VERSION 5.8 ;
BUSBITCHARS "[]" ;
DIVIDERCHAR "/" ;
UNITS
    DATABASE MICRONS 2000 ;
END UNITS

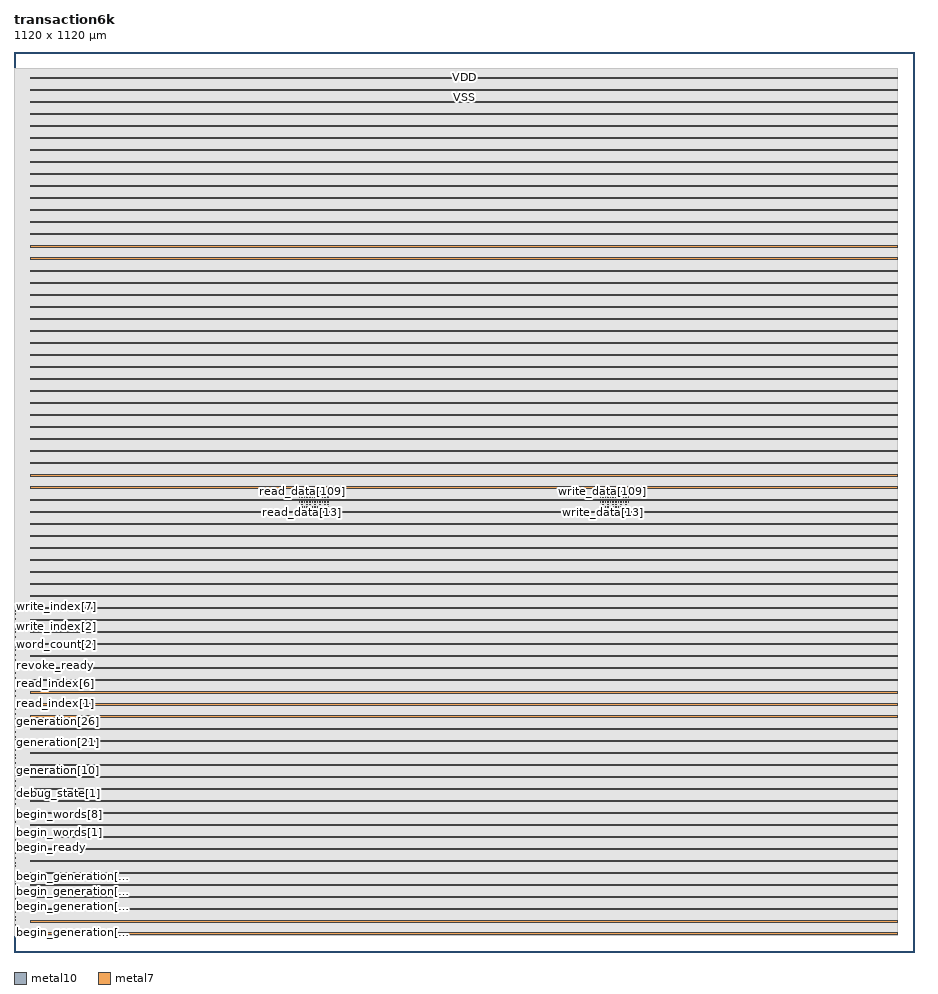
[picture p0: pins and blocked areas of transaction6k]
MACRO transaction6k
  FOREIGN transaction6k 0 0 ;
  CLASS BLOCK ;
  SIZE 1120 BY 1120 ;
  PIN begin_generation[0]
    DIRECTION INPUT ;
    USE SIGNAL ;
    PORT
      LAYER metal10 ;
        RECT  1.295 20.47 2.095 21.27 ;
    END
  END begin_generation[0]
  PIN begin_generation[10]
    DIRECTION INPUT ;
    USE SIGNAL ;
    PORT
      LAYER metal10 ;
        RECT  1.295 52.47 2.095 53.27 ;
    END
  END begin_generation[10]
  PIN begin_generation[11]
    DIRECTION INPUT ;
    USE SIGNAL ;
    PORT
      LAYER metal10 ;
        RECT  1.295 55.67 2.095 56.47 ;
    END
  END begin_generation[11]
  PIN begin_generation[12]
    DIRECTION INPUT ;
    USE SIGNAL ;
    PORT
      LAYER metal10 ;
        RECT  1.295 58.87 2.095 59.67 ;
    END
  END begin_generation[12]
  PIN begin_generation[13]
    DIRECTION INPUT ;
    USE SIGNAL ;
    PORT
      LAYER metal10 ;
        RECT  1.295 62.07 2.095 62.87 ;
    END
  END begin_generation[13]
  PIN begin_generation[14]
    DIRECTION INPUT ;
    USE SIGNAL ;
    PORT
      LAYER metal10 ;
        RECT  1.295 65.27 2.095 66.07 ;
    END
  END begin_generation[14]
  PIN begin_generation[15]
    DIRECTION INPUT ;
    USE SIGNAL ;
    PORT
      LAYER metal10 ;
        RECT  1.295 68.47 2.095 69.27 ;
    END
  END begin_generation[15]
  PIN begin_generation[16]
    DIRECTION INPUT ;
    USE SIGNAL ;
    PORT
      LAYER metal10 ;
        RECT  1.295 71.67 2.095 72.47 ;
    END
  END begin_generation[16]
  PIN begin_generation[17]
    DIRECTION INPUT ;
    USE SIGNAL ;
    PORT
      LAYER metal10 ;
        RECT  1.295 74.87 2.095 75.67 ;
    END
  END begin_generation[17]
  PIN begin_generation[18]
    DIRECTION INPUT ;
    USE SIGNAL ;
    PORT
      LAYER metal10 ;
        RECT  1.295 78.07 2.095 78.87 ;
    END
  END begin_generation[18]
  PIN begin_generation[19]
    DIRECTION INPUT ;
    USE SIGNAL ;
    PORT
      LAYER metal10 ;
        RECT  1.295 81.27 2.095 82.07 ;
    END
  END begin_generation[19]
  PIN begin_generation[1]
    DIRECTION INPUT ;
    USE SIGNAL ;
    PORT
      LAYER metal10 ;
        RECT  1.295 23.67 2.095 24.47 ;
    END
  END begin_generation[1]
  PIN begin_generation[20]
    DIRECTION INPUT ;
    USE SIGNAL ;
    PORT
      LAYER metal10 ;
        RECT  1.295 84.47 2.095 85.27 ;
    END
  END begin_generation[20]
  PIN begin_generation[21]
    DIRECTION INPUT ;
    USE SIGNAL ;
    PORT
      LAYER metal10 ;
        RECT  1.295 87.67 2.095 88.47 ;
    END
  END begin_generation[21]
  PIN begin_generation[22]
    DIRECTION INPUT ;
    USE SIGNAL ;
    PORT
      LAYER metal10 ;
        RECT  1.295 90.87 2.095 91.67 ;
    END
  END begin_generation[22]
  PIN begin_generation[23]
    DIRECTION INPUT ;
    USE SIGNAL ;
    PORT
      LAYER metal10 ;
        RECT  1.295 94.07 2.095 94.87 ;
    END
  END begin_generation[23]
  PIN begin_generation[24]
    DIRECTION INPUT ;
    USE SIGNAL ;
    PORT
      LAYER metal10 ;
        RECT  1.295 97.27 2.095 98.07 ;
    END
  END begin_generation[24]
  PIN begin_generation[25]
    DIRECTION INPUT ;
    USE SIGNAL ;
    PORT
      LAYER metal10 ;
        RECT  1.295 100.47 2.095 101.27 ;
    END
  END begin_generation[25]
  PIN begin_generation[26]
    DIRECTION INPUT ;
    USE SIGNAL ;
    PORT
      LAYER metal10 ;
        RECT  1.295 103.67 2.095 104.47 ;
    END
  END begin_generation[26]
  PIN begin_generation[27]
    DIRECTION INPUT ;
    USE SIGNAL ;
    PORT
      LAYER metal10 ;
        RECT  1.295 106.87 2.095 107.67 ;
    END
  END begin_generation[27]
  PIN begin_generation[28]
    DIRECTION INPUT ;
    USE SIGNAL ;
    PORT
      LAYER metal10 ;
        RECT  1.295 110.07 2.095 110.87 ;
    END
  END begin_generation[28]
  PIN begin_generation[29]
    DIRECTION INPUT ;
    USE SIGNAL ;
    PORT
      LAYER metal10 ;
        RECT  1.295 113.27 2.095 114.07 ;
    END
  END begin_generation[29]
  PIN begin_generation[2]
    DIRECTION INPUT ;
    USE SIGNAL ;
    PORT
      LAYER metal10 ;
        RECT  1.295 26.87 2.095 27.67 ;
    END
  END begin_generation[2]
  PIN begin_generation[30]
    DIRECTION INPUT ;
    USE SIGNAL ;
    PORT
      LAYER metal10 ;
        RECT  1.295 116.47 2.095 117.27 ;
    END
  END begin_generation[30]
  PIN begin_generation[31]
    DIRECTION INPUT ;
    USE SIGNAL ;
    PORT
      LAYER metal10 ;
        RECT  1.295 119.67 2.095 120.47 ;
    END
  END begin_generation[31]
  PIN begin_generation[3]
    DIRECTION INPUT ;
    USE SIGNAL ;
    PORT
      LAYER metal10 ;
        RECT  1.295 30.07 2.095 30.87 ;
    END
  END begin_generation[3]
  PIN begin_generation[4]
    DIRECTION INPUT ;
    USE SIGNAL ;
    PORT
      LAYER metal10 ;
        RECT  1.295 33.27 2.095 34.07 ;
    END
  END begin_generation[4]
  PIN begin_generation[5]
    DIRECTION INPUT ;
    USE SIGNAL ;
    PORT
      LAYER metal10 ;
        RECT  1.295 36.47 2.095 37.27 ;
    END
  END begin_generation[5]
  PIN begin_generation[6]
    DIRECTION INPUT ;
    USE SIGNAL ;
    PORT
      LAYER metal10 ;
        RECT  1.295 39.67 2.095 40.47 ;
    END
  END begin_generation[6]
  PIN begin_generation[7]
    DIRECTION INPUT ;
    USE SIGNAL ;
    PORT
      LAYER metal10 ;
        RECT  1.295 42.87 2.095 43.67 ;
    END
  END begin_generation[7]
  PIN begin_generation[8]
    DIRECTION INPUT ;
    USE SIGNAL ;
    PORT
      LAYER metal10 ;
        RECT  1.295 46.07 2.095 46.87 ;
    END
  END begin_generation[8]
  PIN begin_generation[9]
    DIRECTION INPUT ;
    USE SIGNAL ;
    PORT
      LAYER metal10 ;
        RECT  1.295 49.27 2.095 50.07 ;
    END
  END begin_generation[9]
  PIN begin_owner[0]
    DIRECTION INPUT ;
    USE SIGNAL ;
    PORT
      LAYER metal10 ;
        RECT  1.295 122.87 2.095 123.67 ;
    END
  END begin_owner[0]
  PIN begin_owner[1]
    DIRECTION INPUT ;
    USE SIGNAL ;
    PORT
      LAYER metal10 ;
        RECT  1.295 126.07 2.095 126.87 ;
    END
  END begin_owner[1]
  PIN begin_ready
    DIRECTION OUTPUT ;
    USE SIGNAL ;
    PORT
      LAYER metal10 ;
        RECT  1.295 129.27 2.095 130.07 ;
    END
  END begin_ready
  PIN begin_valid
    DIRECTION INPUT ;
    USE SIGNAL ;
    PORT
      LAYER metal10 ;
        RECT  1.295 132.47 2.095 133.27 ;
    END
  END begin_valid
  PIN begin_words[0]
    DIRECTION INPUT ;
    USE SIGNAL ;
    PORT
      LAYER metal10 ;
        RECT  1.295 135.67 2.095 136.47 ;
    END
  END begin_words[0]
  PIN begin_words[1]
    DIRECTION INPUT ;
    USE SIGNAL ;
    PORT
      LAYER metal10 ;
        RECT  1.295 138.87 2.095 139.67 ;
    END
  END begin_words[1]
  PIN begin_words[2]
    DIRECTION INPUT ;
    USE SIGNAL ;
    PORT
      LAYER metal10 ;
        RECT  1.295 142.07 2.095 142.87 ;
    END
  END begin_words[2]
  PIN begin_words[3]
    DIRECTION INPUT ;
    USE SIGNAL ;
    PORT
      LAYER metal10 ;
        RECT  1.295 145.27 2.095 146.07 ;
    END
  END begin_words[3]
  PIN begin_words[4]
    DIRECTION INPUT ;
    USE SIGNAL ;
    PORT
      LAYER metal10 ;
        RECT  1.295 148.47 2.095 149.27 ;
    END
  END begin_words[4]
  PIN begin_words[5]
    DIRECTION INPUT ;
    USE SIGNAL ;
    PORT
      LAYER metal10 ;
        RECT  1.295 151.67 2.095 152.47 ;
    END
  END begin_words[5]
  PIN begin_words[6]
    DIRECTION INPUT ;
    USE SIGNAL ;
    PORT
      LAYER metal10 ;
        RECT  1.295 154.87 2.095 155.67 ;
    END
  END begin_words[6]
  PIN begin_words[7]
    DIRECTION INPUT ;
    USE SIGNAL ;
    PORT
      LAYER metal10 ;
        RECT  1.295 158.07 2.095 158.87 ;
    END
  END begin_words[7]
  PIN begin_words[8]
    DIRECTION INPUT ;
    USE SIGNAL ;
    PORT
      LAYER metal10 ;
        RECT  1.295 161.27 2.095 162.07 ;
    END
  END begin_words[8]
  PIN begin_words[9]
    DIRECTION INPUT ;
    USE SIGNAL ;
    PORT
      LAYER metal10 ;
        RECT  1.295 164.47 2.095 165.27 ;
    END
  END begin_words[9]
  PIN busy
    DIRECTION OUTPUT ;
    USE SIGNAL ;
    PORT
      LAYER metal10 ;
        RECT  1.295 167.67 2.095 168.47 ;
    END
  END busy
  PIN clk
    DIRECTION INPUT ;
    USE SIGNAL ;
    PORT
      LAYER metal10 ;
        RECT  1.295 170.87 2.095 171.67 ;
    END
  END clk
  PIN commit_ready
    DIRECTION OUTPUT ;
    USE SIGNAL ;
    PORT
      LAYER metal10 ;
        RECT  1.295 174.07 2.095 174.87 ;
    END
  END commit_ready
  PIN commit_valid
    DIRECTION INPUT ;
    USE SIGNAL ;
    PORT
      LAYER metal10 ;
        RECT  1.295 177.27 2.095 178.07 ;
    END
  END commit_valid
  PIN committed
    DIRECTION OUTPUT ;
    USE SIGNAL ;
    PORT
      LAYER metal10 ;
        RECT  1.295 180.47 2.095 181.27 ;
    END
  END committed
  PIN debug_state[0]
    DIRECTION OUTPUT ;
    USE SIGNAL ;
    PORT
      LAYER metal10 ;
        RECT  1.295 183.67 2.095 184.47 ;
    END
  END debug_state[0]
  PIN debug_state[1]
    DIRECTION OUTPUT ;
    USE SIGNAL ;
    PORT
      LAYER metal10 ;
        RECT  1.295 186.87 2.095 187.67 ;
    END
  END debug_state[1]
  PIN debug_state[2]
    DIRECTION OUTPUT ;
    USE SIGNAL ;
    PORT
      LAYER metal10 ;
        RECT  1.295 190.07 2.095 190.87 ;
    END
  END debug_state[2]
  PIN generation[0]
    DIRECTION OUTPUT ;
    USE SIGNAL ;
    PORT
      LAYER metal10 ;
        RECT  1.295 193.27 2.095 194.07 ;
    END
  END generation[0]
  PIN generation[10]
    DIRECTION OUTPUT ;
    USE SIGNAL ;
    PORT
      LAYER metal10 ;
        RECT  1.295 225.27 2.095 226.07 ;
    END
  END generation[10]
  PIN generation[11]
    DIRECTION OUTPUT ;
    USE SIGNAL ;
    PORT
      LAYER metal10 ;
        RECT  1.295 228.47 2.095 229.27 ;
    END
  END generation[11]
  PIN generation[12]
    DIRECTION OUTPUT ;
    USE SIGNAL ;
    PORT
      LAYER metal10 ;
        RECT  1.295 231.67 2.095 232.47 ;
    END
  END generation[12]
  PIN generation[13]
    DIRECTION OUTPUT ;
    USE SIGNAL ;
    PORT
      LAYER metal10 ;
        RECT  1.295 234.87 2.095 235.67 ;
    END
  END generation[13]
  PIN generation[14]
    DIRECTION OUTPUT ;
    USE SIGNAL ;
    PORT
      LAYER metal10 ;
        RECT  1.295 238.07 2.095 238.87 ;
    END
  END generation[14]
  PIN generation[15]
    DIRECTION OUTPUT ;
    USE SIGNAL ;
    PORT
      LAYER metal10 ;
        RECT  1.295 241.27 2.095 242.07 ;
    END
  END generation[15]
  PIN generation[16]
    DIRECTION OUTPUT ;
    USE SIGNAL ;
    PORT
      LAYER metal10 ;
        RECT  1.295 244.47 2.095 245.27 ;
    END
  END generation[16]
  PIN generation[17]
    DIRECTION OUTPUT ;
    USE SIGNAL ;
    PORT
      LAYER metal10 ;
        RECT  1.295 247.67 2.095 248.47 ;
    END
  END generation[17]
  PIN generation[18]
    DIRECTION OUTPUT ;
    USE SIGNAL ;
    PORT
      LAYER metal10 ;
        RECT  1.295 250.87 2.095 251.67 ;
    END
  END generation[18]
  PIN generation[19]
    DIRECTION OUTPUT ;
    USE SIGNAL ;
    PORT
      LAYER metal10 ;
        RECT  1.295 254.07 2.095 254.87 ;
    END
  END generation[19]
  PIN generation[1]
    DIRECTION OUTPUT ;
    USE SIGNAL ;
    PORT
      LAYER metal10 ;
        RECT  1.295 196.47 2.095 197.27 ;
    END
  END generation[1]
  PIN generation[20]
    DIRECTION OUTPUT ;
    USE SIGNAL ;
    PORT
      LAYER metal10 ;
        RECT  1.295 257.27 2.095 258.07 ;
    END
  END generation[20]
  PIN generation[21]
    DIRECTION OUTPUT ;
    USE SIGNAL ;
    PORT
      LAYER metal10 ;
        RECT  1.295 260.47 2.095 261.27 ;
    END
  END generation[21]
  PIN generation[22]
    DIRECTION OUTPUT ;
    USE SIGNAL ;
    PORT
      LAYER metal10 ;
        RECT  1.295 263.67 2.095 264.47 ;
    END
  END generation[22]
  PIN generation[23]
    DIRECTION OUTPUT ;
    USE SIGNAL ;
    PORT
      LAYER metal10 ;
        RECT  1.295 266.87 2.095 267.67 ;
    END
  END generation[23]
  PIN generation[24]
    DIRECTION OUTPUT ;
    USE SIGNAL ;
    PORT
      LAYER metal10 ;
        RECT  1.295 270.07 2.095 270.87 ;
    END
  END generation[24]
  PIN generation[25]
    DIRECTION OUTPUT ;
    USE SIGNAL ;
    PORT
      LAYER metal10 ;
        RECT  1.295 273.27 2.095 274.07 ;
    END
  END generation[25]
  PIN generation[26]
    DIRECTION OUTPUT ;
    USE SIGNAL ;
    PORT
      LAYER metal10 ;
        RECT  1.295 276.47 2.095 277.27 ;
    END
  END generation[26]
  PIN generation[27]
    DIRECTION OUTPUT ;
    USE SIGNAL ;
    PORT
      LAYER metal10 ;
        RECT  1.295 279.67 2.095 280.47 ;
    END
  END generation[27]
  PIN generation[28]
    DIRECTION OUTPUT ;
    USE SIGNAL ;
    PORT
      LAYER metal10 ;
        RECT  1.295 282.87 2.095 283.67 ;
    END
  END generation[28]
  PIN generation[29]
    DIRECTION OUTPUT ;
    USE SIGNAL ;
    PORT
      LAYER metal10 ;
        RECT  1.295 286.07 2.095 286.87 ;
    END
  END generation[29]
  PIN generation[2]
    DIRECTION OUTPUT ;
    USE SIGNAL ;
    PORT
      LAYER metal10 ;
        RECT  1.295 199.67 2.095 200.47 ;
    END
  END generation[2]
  PIN generation[30]
    DIRECTION OUTPUT ;
    USE SIGNAL ;
    PORT
      LAYER metal10 ;
        RECT  1.295 289.27 2.095 290.07 ;
    END
  END generation[30]
  PIN generation[31]
    DIRECTION OUTPUT ;
    USE SIGNAL ;
    PORT
      LAYER metal10 ;
        RECT  1.295 292.47 2.095 293.27 ;
    END
  END generation[31]
  PIN generation[3]
    DIRECTION OUTPUT ;
    USE SIGNAL ;
    PORT
      LAYER metal10 ;
        RECT  1.295 202.87 2.095 203.67 ;
    END
  END generation[3]
  PIN generation[4]
    DIRECTION OUTPUT ;
    USE SIGNAL ;
    PORT
      LAYER metal10 ;
        RECT  1.295 206.07 2.095 206.87 ;
    END
  END generation[4]
  PIN generation[5]
    DIRECTION OUTPUT ;
    USE SIGNAL ;
    PORT
      LAYER metal10 ;
        RECT  1.295 209.27 2.095 210.07 ;
    END
  END generation[5]
  PIN generation[6]
    DIRECTION OUTPUT ;
    USE SIGNAL ;
    PORT
      LAYER metal10 ;
        RECT  1.295 212.47 2.095 213.27 ;
    END
  END generation[6]
  PIN generation[7]
    DIRECTION OUTPUT ;
    USE SIGNAL ;
    PORT
      LAYER metal10 ;
        RECT  1.295 215.67 2.095 216.47 ;
    END
  END generation[7]
  PIN generation[8]
    DIRECTION OUTPUT ;
    USE SIGNAL ;
    PORT
      LAYER metal10 ;
        RECT  1.295 218.87 2.095 219.67 ;
    END
  END generation[8]
  PIN generation[9]
    DIRECTION OUTPUT ;
    USE SIGNAL ;
    PORT
      LAYER metal10 ;
        RECT  1.295 222.07 2.095 222.87 ;
    END
  END generation[9]
  PIN owner[0]
    DIRECTION OUTPUT ;
    USE SIGNAL ;
    PORT
      LAYER metal10 ;
        RECT  1.295 295.67 2.095 296.47 ;
    END
  END owner[0]
  PIN owner[1]
    DIRECTION OUTPUT ;
    USE SIGNAL ;
    PORT
      LAYER metal10 ;
        RECT  1.295 298.87 2.095 299.67 ;
    END
  END owner[1]
  PIN protocol_error
    DIRECTION OUTPUT ;
    USE SIGNAL ;
    PORT
      LAYER metal10 ;
        RECT  1.295 302.07 2.095 302.87 ;
    END
  END protocol_error
  PIN read_data[0]
    DIRECTION OUTPUT ;
    USE SIGNAL ;
    PORT
      LAYER metal10 ;
        RECT  354.895 543.67 355.695 544.47 ;
    END
  END read_data[0]
  PIN read_data[100]
    DIRECTION OUTPUT ;
    USE SIGNAL ;
    PORT
      LAYER metal10 ;
        RECT  367.695 569.27 368.495 570.07 ;
    END
  END read_data[100]
  PIN read_data[101]
    DIRECTION OUTPUT ;
    USE SIGNAL ;
    PORT
      LAYER metal10 ;
        RECT  370.895 569.27 371.695 570.07 ;
    END
  END read_data[101]
  PIN read_data[102]
    DIRECTION OUTPUT ;
    USE SIGNAL ;
    PORT
      LAYER metal10 ;
        RECT  374.095 569.27 374.895 570.07 ;
    END
  END read_data[102]
  PIN read_data[103]
    DIRECTION OUTPUT ;
    USE SIGNAL ;
    PORT
      LAYER metal10 ;
        RECT  377.295 569.27 378.095 570.07 ;
    END
  END read_data[103]
  PIN read_data[104]
    DIRECTION OUTPUT ;
    USE SIGNAL ;
    PORT
      LAYER metal10 ;
        RECT  380.495 569.27 381.295 570.07 ;
    END
  END read_data[104]
  PIN read_data[105]
    DIRECTION OUTPUT ;
    USE SIGNAL ;
    PORT
      LAYER metal10 ;
        RECT  383.695 569.27 384.495 570.07 ;
    END
  END read_data[105]
  PIN read_data[106]
    DIRECTION OUTPUT ;
    USE SIGNAL ;
    PORT
      LAYER metal10 ;
        RECT  386.895 569.27 387.695 570.07 ;
    END
  END read_data[106]
  PIN read_data[107]
    DIRECTION OUTPUT ;
    USE SIGNAL ;
    PORT
      LAYER metal10 ;
        RECT  390.095 569.27 390.895 570.07 ;
    END
  END read_data[107]
  PIN read_data[108]
    DIRECTION OUTPUT ;
    USE SIGNAL ;
    PORT
      LAYER metal10 ;
        RECT  354.895 572.47 355.695 573.27 ;
    END
  END read_data[108]
  PIN read_data[109]
    DIRECTION OUTPUT ;
    USE SIGNAL ;
    PORT
      LAYER metal10 ;
        RECT  358.095 572.47 358.895 573.27 ;
    END
  END read_data[109]
  PIN read_data[10]
    DIRECTION OUTPUT ;
    USE SIGNAL ;
    PORT
      LAYER metal10 ;
        RECT  386.895 543.67 387.695 544.47 ;
    END
  END read_data[10]
  PIN read_data[110]
    DIRECTION OUTPUT ;
    USE SIGNAL ;
    PORT
      LAYER metal10 ;
        RECT  361.295 572.47 362.095 573.27 ;
    END
  END read_data[110]
  PIN read_data[111]
    DIRECTION OUTPUT ;
    USE SIGNAL ;
    PORT
      LAYER metal10 ;
        RECT  364.495 572.47 365.295 573.27 ;
    END
  END read_data[111]
  PIN read_data[112]
    DIRECTION OUTPUT ;
    USE SIGNAL ;
    PORT
      LAYER metal10 ;
        RECT  367.695 572.47 368.495 573.27 ;
    END
  END read_data[112]
  PIN read_data[113]
    DIRECTION OUTPUT ;
    USE SIGNAL ;
    PORT
      LAYER metal10 ;
        RECT  370.895 572.47 371.695 573.27 ;
    END
  END read_data[113]
  PIN read_data[114]
    DIRECTION OUTPUT ;
    USE SIGNAL ;
    PORT
      LAYER metal10 ;
        RECT  374.095 572.47 374.895 573.27 ;
    END
  END read_data[114]
  PIN read_data[115]
    DIRECTION OUTPUT ;
    USE SIGNAL ;
    PORT
      LAYER metal10 ;
        RECT  377.295 572.47 378.095 573.27 ;
    END
  END read_data[115]
  PIN read_data[116]
    DIRECTION OUTPUT ;
    USE SIGNAL ;
    PORT
      LAYER metal10 ;
        RECT  380.495 572.47 381.295 573.27 ;
    END
  END read_data[116]
  PIN read_data[117]
    DIRECTION OUTPUT ;
    USE SIGNAL ;
    PORT
      LAYER metal10 ;
        RECT  383.695 572.47 384.495 573.27 ;
    END
  END read_data[117]
  PIN read_data[118]
    DIRECTION OUTPUT ;
    USE SIGNAL ;
    PORT
      LAYER metal10 ;
        RECT  386.895 572.47 387.695 573.27 ;
    END
  END read_data[118]
  PIN read_data[119]
    DIRECTION OUTPUT ;
    USE SIGNAL ;
    PORT
      LAYER metal10 ;
        RECT  390.095 572.47 390.895 573.27 ;
    END
  END read_data[119]
  PIN read_data[11]
    DIRECTION OUTPUT ;
    USE SIGNAL ;
    PORT
      LAYER metal10 ;
        RECT  390.095 543.67 390.895 544.47 ;
    END
  END read_data[11]
  PIN read_data[120]
    DIRECTION OUTPUT ;
    USE SIGNAL ;
    PORT
      LAYER metal10 ;
        RECT  354.895 575.67 355.695 576.47 ;
    END
  END read_data[120]
  PIN read_data[121]
    DIRECTION OUTPUT ;
    USE SIGNAL ;
    PORT
      LAYER metal10 ;
        RECT  358.095 575.67 358.895 576.47 ;
    END
  END read_data[121]
  PIN read_data[122]
    DIRECTION OUTPUT ;
    USE SIGNAL ;
    PORT
      LAYER metal10 ;
        RECT  361.295 575.67 362.095 576.47 ;
    END
  END read_data[122]
  PIN read_data[123]
    DIRECTION OUTPUT ;
    USE SIGNAL ;
    PORT
      LAYER metal10 ;
        RECT  364.495 575.67 365.295 576.47 ;
    END
  END read_data[123]
  PIN read_data[124]
    DIRECTION OUTPUT ;
    USE SIGNAL ;
    PORT
      LAYER metal10 ;
        RECT  367.695 575.67 368.495 576.47 ;
    END
  END read_data[124]
  PIN read_data[125]
    DIRECTION OUTPUT ;
    USE SIGNAL ;
    PORT
      LAYER metal10 ;
        RECT  370.895 575.67 371.695 576.47 ;
    END
  END read_data[125]
  PIN read_data[126]
    DIRECTION OUTPUT ;
    USE SIGNAL ;
    PORT
      LAYER metal10 ;
        RECT  374.095 575.67 374.895 576.47 ;
    END
  END read_data[126]
  PIN read_data[127]
    DIRECTION OUTPUT ;
    USE SIGNAL ;
    PORT
      LAYER metal10 ;
        RECT  377.295 575.67 378.095 576.47 ;
    END
  END read_data[127]
  PIN read_data[12]
    DIRECTION OUTPUT ;
    USE SIGNAL ;
    PORT
      LAYER metal10 ;
        RECT  354.895 546.87 355.695 547.67 ;
    END
  END read_data[12]
  PIN read_data[13]
    DIRECTION OUTPUT ;
    USE SIGNAL ;
    PORT
      LAYER metal10 ;
        RECT  358.095 546.87 358.895 547.67 ;
    END
  END read_data[13]
  PIN read_data[14]
    DIRECTION OUTPUT ;
    USE SIGNAL ;
    PORT
      LAYER metal10 ;
        RECT  361.295 546.87 362.095 547.67 ;
    END
  END read_data[14]
  PIN read_data[15]
    DIRECTION OUTPUT ;
    USE SIGNAL ;
    PORT
      LAYER metal10 ;
        RECT  364.495 546.87 365.295 547.67 ;
    END
  END read_data[15]
  PIN read_data[16]
    DIRECTION OUTPUT ;
    USE SIGNAL ;
    PORT
      LAYER metal10 ;
        RECT  367.695 546.87 368.495 547.67 ;
    END
  END read_data[16]
  PIN read_data[17]
    DIRECTION OUTPUT ;
    USE SIGNAL ;
    PORT
      LAYER metal10 ;
        RECT  370.895 546.87 371.695 547.67 ;
    END
  END read_data[17]
  PIN read_data[18]
    DIRECTION OUTPUT ;
    USE SIGNAL ;
    PORT
      LAYER metal10 ;
        RECT  374.095 546.87 374.895 547.67 ;
    END
  END read_data[18]
  PIN read_data[19]
    DIRECTION OUTPUT ;
    USE SIGNAL ;
    PORT
      LAYER metal10 ;
        RECT  377.295 546.87 378.095 547.67 ;
    END
  END read_data[19]
  PIN read_data[1]
    DIRECTION OUTPUT ;
    USE SIGNAL ;
    PORT
      LAYER metal10 ;
        RECT  358.095 543.67 358.895 544.47 ;
    END
  END read_data[1]
  PIN read_data[20]
    DIRECTION OUTPUT ;
    USE SIGNAL ;
    PORT
      LAYER metal10 ;
        RECT  380.495 546.87 381.295 547.67 ;
    END
  END read_data[20]
  PIN read_data[21]
    DIRECTION OUTPUT ;
    USE SIGNAL ;
    PORT
      LAYER metal10 ;
        RECT  383.695 546.87 384.495 547.67 ;
    END
  END read_data[21]
  PIN read_data[22]
    DIRECTION OUTPUT ;
    USE SIGNAL ;
    PORT
      LAYER metal10 ;
        RECT  386.895 546.87 387.695 547.67 ;
    END
  END read_data[22]
  PIN read_data[23]
    DIRECTION OUTPUT ;
    USE SIGNAL ;
    PORT
      LAYER metal10 ;
        RECT  390.095 546.87 390.895 547.67 ;
    END
  END read_data[23]
  PIN read_data[24]
    DIRECTION OUTPUT ;
    USE SIGNAL ;
    PORT
      LAYER metal10 ;
        RECT  354.895 550.07 355.695 550.87 ;
    END
  END read_data[24]
  PIN read_data[25]
    DIRECTION OUTPUT ;
    USE SIGNAL ;
    PORT
      LAYER metal10 ;
        RECT  358.095 550.07 358.895 550.87 ;
    END
  END read_data[25]
  PIN read_data[26]
    DIRECTION OUTPUT ;
    USE SIGNAL ;
    PORT
      LAYER metal10 ;
        RECT  361.295 550.07 362.095 550.87 ;
    END
  END read_data[26]
  PIN read_data[27]
    DIRECTION OUTPUT ;
    USE SIGNAL ;
    PORT
      LAYER metal10 ;
        RECT  364.495 550.07 365.295 550.87 ;
    END
  END read_data[27]
  PIN read_data[28]
    DIRECTION OUTPUT ;
    USE SIGNAL ;
    PORT
      LAYER metal10 ;
        RECT  367.695 550.07 368.495 550.87 ;
    END
  END read_data[28]
  PIN read_data[29]
    DIRECTION OUTPUT ;
    USE SIGNAL ;
    PORT
      LAYER metal10 ;
        RECT  370.895 550.07 371.695 550.87 ;
    END
  END read_data[29]
  PIN read_data[2]
    DIRECTION OUTPUT ;
    USE SIGNAL ;
    PORT
      LAYER metal10 ;
        RECT  361.295 543.67 362.095 544.47 ;
    END
  END read_data[2]
  PIN read_data[30]
    DIRECTION OUTPUT ;
    USE SIGNAL ;
    PORT
      LAYER metal10 ;
        RECT  374.095 550.07 374.895 550.87 ;
    END
  END read_data[30]
  PIN read_data[31]
    DIRECTION OUTPUT ;
    USE SIGNAL ;
    PORT
      LAYER metal10 ;
        RECT  377.295 550.07 378.095 550.87 ;
    END
  END read_data[31]
  PIN read_data[32]
    DIRECTION OUTPUT ;
    USE SIGNAL ;
    PORT
      LAYER metal10 ;
        RECT  380.495 550.07 381.295 550.87 ;
    END
  END read_data[32]
  PIN read_data[33]
    DIRECTION OUTPUT ;
    USE SIGNAL ;
    PORT
      LAYER metal10 ;
        RECT  383.695 550.07 384.495 550.87 ;
    END
  END read_data[33]
  PIN read_data[34]
    DIRECTION OUTPUT ;
    USE SIGNAL ;
    PORT
      LAYER metal10 ;
        RECT  386.895 550.07 387.695 550.87 ;
    END
  END read_data[34]
  PIN read_data[35]
    DIRECTION OUTPUT ;
    USE SIGNAL ;
    PORT
      LAYER metal10 ;
        RECT  390.095 550.07 390.895 550.87 ;
    END
  END read_data[35]
  PIN read_data[36]
    DIRECTION OUTPUT ;
    USE SIGNAL ;
    PORT
      LAYER metal10 ;
        RECT  354.895 553.27 355.695 554.07 ;
    END
  END read_data[36]
  PIN read_data[37]
    DIRECTION OUTPUT ;
    USE SIGNAL ;
    PORT
      LAYER metal10 ;
        RECT  358.095 553.27 358.895 554.07 ;
    END
  END read_data[37]
  PIN read_data[38]
    DIRECTION OUTPUT ;
    USE SIGNAL ;
    PORT
      LAYER metal10 ;
        RECT  361.295 553.27 362.095 554.07 ;
    END
  END read_data[38]
  PIN read_data[39]
    DIRECTION OUTPUT ;
    USE SIGNAL ;
    PORT
      LAYER metal10 ;
        RECT  364.495 553.27 365.295 554.07 ;
    END
  END read_data[39]
  PIN read_data[3]
    DIRECTION OUTPUT ;
    USE SIGNAL ;
    PORT
      LAYER metal10 ;
        RECT  364.495 543.67 365.295 544.47 ;
    END
  END read_data[3]
  PIN read_data[40]
    DIRECTION OUTPUT ;
    USE SIGNAL ;
    PORT
      LAYER metal10 ;
        RECT  367.695 553.27 368.495 554.07 ;
    END
  END read_data[40]
  PIN read_data[41]
    DIRECTION OUTPUT ;
    USE SIGNAL ;
    PORT
      LAYER metal10 ;
        RECT  370.895 553.27 371.695 554.07 ;
    END
  END read_data[41]
  PIN read_data[42]
    DIRECTION OUTPUT ;
    USE SIGNAL ;
    PORT
      LAYER metal10 ;
        RECT  374.095 553.27 374.895 554.07 ;
    END
  END read_data[42]
  PIN read_data[43]
    DIRECTION OUTPUT ;
    USE SIGNAL ;
    PORT
      LAYER metal10 ;
        RECT  377.295 553.27 378.095 554.07 ;
    END
  END read_data[43]
  PIN read_data[44]
    DIRECTION OUTPUT ;
    USE SIGNAL ;
    PORT
      LAYER metal10 ;
        RECT  380.495 553.27 381.295 554.07 ;
    END
  END read_data[44]
  PIN read_data[45]
    DIRECTION OUTPUT ;
    USE SIGNAL ;
    PORT
      LAYER metal10 ;
        RECT  383.695 553.27 384.495 554.07 ;
    END
  END read_data[45]
  PIN read_data[46]
    DIRECTION OUTPUT ;
    USE SIGNAL ;
    PORT
      LAYER metal10 ;
        RECT  386.895 553.27 387.695 554.07 ;
    END
  END read_data[46]
  PIN read_data[47]
    DIRECTION OUTPUT ;
    USE SIGNAL ;
    PORT
      LAYER metal10 ;
        RECT  390.095 553.27 390.895 554.07 ;
    END
  END read_data[47]
  PIN read_data[48]
    DIRECTION OUTPUT ;
    USE SIGNAL ;
    PORT
      LAYER metal10 ;
        RECT  354.895 556.47 355.695 557.27 ;
    END
  END read_data[48]
  PIN read_data[49]
    DIRECTION OUTPUT ;
    USE SIGNAL ;
    PORT
      LAYER metal10 ;
        RECT  358.095 556.47 358.895 557.27 ;
    END
  END read_data[49]
  PIN read_data[4]
    DIRECTION OUTPUT ;
    USE SIGNAL ;
    PORT
      LAYER metal10 ;
        RECT  367.695 543.67 368.495 544.47 ;
    END
  END read_data[4]
  PIN read_data[50]
    DIRECTION OUTPUT ;
    USE SIGNAL ;
    PORT
      LAYER metal10 ;
        RECT  361.295 556.47 362.095 557.27 ;
    END
  END read_data[50]
  PIN read_data[51]
    DIRECTION OUTPUT ;
    USE SIGNAL ;
    PORT
      LAYER metal10 ;
        RECT  364.495 556.47 365.295 557.27 ;
    END
  END read_data[51]
  PIN read_data[52]
    DIRECTION OUTPUT ;
    USE SIGNAL ;
    PORT
      LAYER metal10 ;
        RECT  367.695 556.47 368.495 557.27 ;
    END
  END read_data[52]
  PIN read_data[53]
    DIRECTION OUTPUT ;
    USE SIGNAL ;
    PORT
      LAYER metal10 ;
        RECT  370.895 556.47 371.695 557.27 ;
    END
  END read_data[53]
  PIN read_data[54]
    DIRECTION OUTPUT ;
    USE SIGNAL ;
    PORT
      LAYER metal10 ;
        RECT  374.095 556.47 374.895 557.27 ;
    END
  END read_data[54]
  PIN read_data[55]
    DIRECTION OUTPUT ;
    USE SIGNAL ;
    PORT
      LAYER metal10 ;
        RECT  377.295 556.47 378.095 557.27 ;
    END
  END read_data[55]
  PIN read_data[56]
    DIRECTION OUTPUT ;
    USE SIGNAL ;
    PORT
      LAYER metal10 ;
        RECT  380.495 556.47 381.295 557.27 ;
    END
  END read_data[56]
  PIN read_data[57]
    DIRECTION OUTPUT ;
    USE SIGNAL ;
    PORT
      LAYER metal10 ;
        RECT  383.695 556.47 384.495 557.27 ;
    END
  END read_data[57]
  PIN read_data[58]
    DIRECTION OUTPUT ;
    USE SIGNAL ;
    PORT
      LAYER metal10 ;
        RECT  386.895 556.47 387.695 557.27 ;
    END
  END read_data[58]
  PIN read_data[59]
    DIRECTION OUTPUT ;
    USE SIGNAL ;
    PORT
      LAYER metal10 ;
        RECT  390.095 556.47 390.895 557.27 ;
    END
  END read_data[59]
  PIN read_data[5]
    DIRECTION OUTPUT ;
    USE SIGNAL ;
    PORT
      LAYER metal10 ;
        RECT  370.895 543.67 371.695 544.47 ;
    END
  END read_data[5]
  PIN read_data[60]
    DIRECTION OUTPUT ;
    USE SIGNAL ;
    PORT
      LAYER metal10 ;
        RECT  354.895 559.67 355.695 560.47 ;
    END
  END read_data[60]
  PIN read_data[61]
    DIRECTION OUTPUT ;
    USE SIGNAL ;
    PORT
      LAYER metal10 ;
        RECT  358.095 559.67 358.895 560.47 ;
    END
  END read_data[61]
  PIN read_data[62]
    DIRECTION OUTPUT ;
    USE SIGNAL ;
    PORT
      LAYER metal10 ;
        RECT  361.295 559.67 362.095 560.47 ;
    END
  END read_data[62]
  PIN read_data[63]
    DIRECTION OUTPUT ;
    USE SIGNAL ;
    PORT
      LAYER metal10 ;
        RECT  364.495 559.67 365.295 560.47 ;
    END
  END read_data[63]
  PIN read_data[64]
    DIRECTION OUTPUT ;
    USE SIGNAL ;
    PORT
      LAYER metal10 ;
        RECT  367.695 559.67 368.495 560.47 ;
    END
  END read_data[64]
  PIN read_data[65]
    DIRECTION OUTPUT ;
    USE SIGNAL ;
    PORT
      LAYER metal10 ;
        RECT  370.895 559.67 371.695 560.47 ;
    END
  END read_data[65]
  PIN read_data[66]
    DIRECTION OUTPUT ;
    USE SIGNAL ;
    PORT
      LAYER metal10 ;
        RECT  374.095 559.67 374.895 560.47 ;
    END
  END read_data[66]
  PIN read_data[67]
    DIRECTION OUTPUT ;
    USE SIGNAL ;
    PORT
      LAYER metal10 ;
        RECT  377.295 559.67 378.095 560.47 ;
    END
  END read_data[67]
  PIN read_data[68]
    DIRECTION OUTPUT ;
    USE SIGNAL ;
    PORT
      LAYER metal10 ;
        RECT  380.495 559.67 381.295 560.47 ;
    END
  END read_data[68]
  PIN read_data[69]
    DIRECTION OUTPUT ;
    USE SIGNAL ;
    PORT
      LAYER metal10 ;
        RECT  383.695 559.67 384.495 560.47 ;
    END
  END read_data[69]
  PIN read_data[6]
    DIRECTION OUTPUT ;
    USE SIGNAL ;
    PORT
      LAYER metal10 ;
        RECT  374.095 543.67 374.895 544.47 ;
    END
  END read_data[6]
  PIN read_data[70]
    DIRECTION OUTPUT ;
    USE SIGNAL ;
    PORT
      LAYER metal10 ;
        RECT  386.895 559.67 387.695 560.47 ;
    END
  END read_data[70]
  PIN read_data[71]
    DIRECTION OUTPUT ;
    USE SIGNAL ;
    PORT
      LAYER metal10 ;
        RECT  390.095 559.67 390.895 560.47 ;
    END
  END read_data[71]
  PIN read_data[72]
    DIRECTION OUTPUT ;
    USE SIGNAL ;
    PORT
      LAYER metal10 ;
        RECT  354.895 562.87 355.695 563.67 ;
    END
  END read_data[72]
  PIN read_data[73]
    DIRECTION OUTPUT ;
    USE SIGNAL ;
    PORT
      LAYER metal10 ;
        RECT  358.095 562.87 358.895 563.67 ;
    END
  END read_data[73]
  PIN read_data[74]
    DIRECTION OUTPUT ;
    USE SIGNAL ;
    PORT
      LAYER metal10 ;
        RECT  361.295 562.87 362.095 563.67 ;
    END
  END read_data[74]
  PIN read_data[75]
    DIRECTION OUTPUT ;
    USE SIGNAL ;
    PORT
      LAYER metal10 ;
        RECT  364.495 562.87 365.295 563.67 ;
    END
  END read_data[75]
  PIN read_data[76]
    DIRECTION OUTPUT ;
    USE SIGNAL ;
    PORT
      LAYER metal10 ;
        RECT  367.695 562.87 368.495 563.67 ;
    END
  END read_data[76]
  PIN read_data[77]
    DIRECTION OUTPUT ;
    USE SIGNAL ;
    PORT
      LAYER metal10 ;
        RECT  370.895 562.87 371.695 563.67 ;
    END
  END read_data[77]
  PIN read_data[78]
    DIRECTION OUTPUT ;
    USE SIGNAL ;
    PORT
      LAYER metal10 ;
        RECT  374.095 562.87 374.895 563.67 ;
    END
  END read_data[78]
  PIN read_data[79]
    DIRECTION OUTPUT ;
    USE SIGNAL ;
    PORT
      LAYER metal10 ;
        RECT  377.295 562.87 378.095 563.67 ;
    END
  END read_data[79]
  PIN read_data[7]
    DIRECTION OUTPUT ;
    USE SIGNAL ;
    PORT
      LAYER metal10 ;
        RECT  377.295 543.67 378.095 544.47 ;
    END
  END read_data[7]
  PIN read_data[80]
    DIRECTION OUTPUT ;
    USE SIGNAL ;
    PORT
      LAYER metal10 ;
        RECT  380.495 562.87 381.295 563.67 ;
    END
  END read_data[80]
  PIN read_data[81]
    DIRECTION OUTPUT ;
    USE SIGNAL ;
    PORT
      LAYER metal10 ;
        RECT  383.695 562.87 384.495 563.67 ;
    END
  END read_data[81]
  PIN read_data[82]
    DIRECTION OUTPUT ;
    USE SIGNAL ;
    PORT
      LAYER metal10 ;
        RECT  386.895 562.87 387.695 563.67 ;
    END
  END read_data[82]
  PIN read_data[83]
    DIRECTION OUTPUT ;
    USE SIGNAL ;
    PORT
      LAYER metal10 ;
        RECT  390.095 562.87 390.895 563.67 ;
    END
  END read_data[83]
  PIN read_data[84]
    DIRECTION OUTPUT ;
    USE SIGNAL ;
    PORT
      LAYER metal10 ;
        RECT  354.895 566.07 355.695 566.87 ;
    END
  END read_data[84]
  PIN read_data[85]
    DIRECTION OUTPUT ;
    USE SIGNAL ;
    PORT
      LAYER metal10 ;
        RECT  358.095 566.07 358.895 566.87 ;
    END
  END read_data[85]
  PIN read_data[86]
    DIRECTION OUTPUT ;
    USE SIGNAL ;
    PORT
      LAYER metal10 ;
        RECT  361.295 566.07 362.095 566.87 ;
    END
  END read_data[86]
  PIN read_data[87]
    DIRECTION OUTPUT ;
    USE SIGNAL ;
    PORT
      LAYER metal10 ;
        RECT  364.495 566.07 365.295 566.87 ;
    END
  END read_data[87]
  PIN read_data[88]
    DIRECTION OUTPUT ;
    USE SIGNAL ;
    PORT
      LAYER metal10 ;
        RECT  367.695 566.07 368.495 566.87 ;
    END
  END read_data[88]
  PIN read_data[89]
    DIRECTION OUTPUT ;
    USE SIGNAL ;
    PORT
      LAYER metal10 ;
        RECT  370.895 566.07 371.695 566.87 ;
    END
  END read_data[89]
  PIN read_data[8]
    DIRECTION OUTPUT ;
    USE SIGNAL ;
    PORT
      LAYER metal10 ;
        RECT  380.495 543.67 381.295 544.47 ;
    END
  END read_data[8]
  PIN read_data[90]
    DIRECTION OUTPUT ;
    USE SIGNAL ;
    PORT
      LAYER metal10 ;
        RECT  374.095 566.07 374.895 566.87 ;
    END
  END read_data[90]
  PIN read_data[91]
    DIRECTION OUTPUT ;
    USE SIGNAL ;
    PORT
      LAYER metal10 ;
        RECT  377.295 566.07 378.095 566.87 ;
    END
  END read_data[91]
  PIN read_data[92]
    DIRECTION OUTPUT ;
    USE SIGNAL ;
    PORT
      LAYER metal10 ;
        RECT  380.495 566.07 381.295 566.87 ;
    END
  END read_data[92]
  PIN read_data[93]
    DIRECTION OUTPUT ;
    USE SIGNAL ;
    PORT
      LAYER metal10 ;
        RECT  383.695 566.07 384.495 566.87 ;
    END
  END read_data[93]
  PIN read_data[94]
    DIRECTION OUTPUT ;
    USE SIGNAL ;
    PORT
      LAYER metal10 ;
        RECT  386.895 566.07 387.695 566.87 ;
    END
  END read_data[94]
  PIN read_data[95]
    DIRECTION OUTPUT ;
    USE SIGNAL ;
    PORT
      LAYER metal10 ;
        RECT  390.095 566.07 390.895 566.87 ;
    END
  END read_data[95]
  PIN read_data[96]
    DIRECTION OUTPUT ;
    USE SIGNAL ;
    PORT
      LAYER metal10 ;
        RECT  354.895 569.27 355.695 570.07 ;
    END
  END read_data[96]
  PIN read_data[97]
    DIRECTION OUTPUT ;
    USE SIGNAL ;
    PORT
      LAYER metal10 ;
        RECT  358.095 569.27 358.895 570.07 ;
    END
  END read_data[97]
  PIN read_data[98]
    DIRECTION OUTPUT ;
    USE SIGNAL ;
    PORT
      LAYER metal10 ;
        RECT  361.295 569.27 362.095 570.07 ;
    END
  END read_data[98]
  PIN read_data[99]
    DIRECTION OUTPUT ;
    USE SIGNAL ;
    PORT
      LAYER metal10 ;
        RECT  364.495 569.27 365.295 570.07 ;
    END
  END read_data[99]
  PIN read_data[9]
    DIRECTION OUTPUT ;
    USE SIGNAL ;
    PORT
      LAYER metal10 ;
        RECT  383.695 543.67 384.495 544.47 ;
    END
  END read_data[9]
  PIN read_index[0]
    DIRECTION OUTPUT ;
    USE SIGNAL ;
    PORT
      LAYER metal10 ;
        RECT  1.295 305.27 2.095 306.07 ;
    END
  END read_index[0]
  PIN read_index[1]
    DIRECTION OUTPUT ;
    USE SIGNAL ;
    PORT
      LAYER metal10 ;
        RECT  1.295 308.47 2.095 309.27 ;
    END
  END read_index[1]
  PIN read_index[2]
    DIRECTION OUTPUT ;
    USE SIGNAL ;
    PORT
      LAYER metal10 ;
        RECT  1.295 311.67 2.095 312.47 ;
    END
  END read_index[2]
  PIN read_index[3]
    DIRECTION OUTPUT ;
    USE SIGNAL ;
    PORT
      LAYER metal10 ;
        RECT  1.295 314.87 2.095 315.67 ;
    END
  END read_index[3]
  PIN read_index[4]
    DIRECTION OUTPUT ;
    USE SIGNAL ;
    PORT
      LAYER metal10 ;
        RECT  1.295 318.07 2.095 318.87 ;
    END
  END read_index[4]
  PIN read_index[5]
    DIRECTION OUTPUT ;
    USE SIGNAL ;
    PORT
      LAYER metal10 ;
        RECT  1.295 321.27 2.095 322.07 ;
    END
  END read_index[5]
  PIN read_index[6]
    DIRECTION OUTPUT ;
    USE SIGNAL ;
    PORT
      LAYER metal10 ;
        RECT  1.295 324.47 2.095 325.27 ;
    END
  END read_index[6]
  PIN read_index[7]
    DIRECTION OUTPUT ;
    USE SIGNAL ;
    PORT
      LAYER metal10 ;
        RECT  1.295 327.67 2.095 328.47 ;
    END
  END read_index[7]
  PIN read_index[8]
    DIRECTION OUTPUT ;
    USE SIGNAL ;
    PORT
      LAYER metal10 ;
        RECT  1.295 330.87 2.095 331.67 ;
    END
  END read_index[8]
  PIN read_index[9]
    DIRECTION OUTPUT ;
    USE SIGNAL ;
    PORT
      LAYER metal10 ;
        RECT  1.295 334.07 2.095 334.87 ;
    END
  END read_index[9]
  PIN read_last
    DIRECTION OUTPUT ;
    USE SIGNAL ;
    PORT
      LAYER metal10 ;
        RECT  1.295 337.27 2.095 338.07 ;
    END
  END read_last
  PIN read_take
    DIRECTION INPUT ;
    USE SIGNAL ;
    PORT
      LAYER metal10 ;
        RECT  1.295 340.47 2.095 341.27 ;
    END
  END read_take
  PIN read_valid
    DIRECTION OUTPUT ;
    USE SIGNAL ;
    PORT
      LAYER metal10 ;
        RECT  1.295 343.67 2.095 344.47 ;
    END
  END read_valid
  PIN release_ready
    DIRECTION OUTPUT ;
    USE SIGNAL ;
    PORT
      LAYER metal10 ;
        RECT  1.295 346.87 2.095 347.67 ;
    END
  END release_ready
  PIN release_valid
    DIRECTION INPUT ;
    USE SIGNAL ;
    PORT
      LAYER metal10 ;
        RECT  1.295 350.07 2.095 350.87 ;
    END
  END release_valid
  PIN reset
    DIRECTION INPUT ;
    USE SIGNAL ;
    PORT
      LAYER metal10 ;
        RECT  1.295 353.27 2.095 354.07 ;
    END
  END reset
  PIN revoke_ready
    DIRECTION OUTPUT ;
    USE SIGNAL ;
    PORT
      LAYER metal10 ;
        RECT  1.295 356.47 2.095 357.27 ;
    END
  END revoke_ready
  PIN revoke_valid
    DIRECTION INPUT ;
    USE SIGNAL ;
    PORT
      LAYER metal10 ;
        RECT  1.295 359.67 2.095 360.47 ;
    END
  END revoke_valid
  PIN sealed
    DIRECTION OUTPUT ;
    USE SIGNAL ;
    PORT
      LAYER metal10 ;
        RECT  1.295 362.87 2.095 363.67 ;
    END
  END sealed
  PIN word_count[0]
    DIRECTION OUTPUT ;
    USE SIGNAL ;
    PORT
      LAYER metal10 ;
        RECT  1.295 366.07 2.095 366.87 ;
    END
  END word_count[0]
  PIN word_count[1]
    DIRECTION OUTPUT ;
    USE SIGNAL ;
    PORT
      LAYER metal10 ;
        RECT  1.295 369.27 2.095 370.07 ;
    END
  END word_count[1]
  PIN word_count[2]
    DIRECTION OUTPUT ;
    USE SIGNAL ;
    PORT
      LAYER metal10 ;
        RECT  1.295 372.47 2.095 373.27 ;
    END
  END word_count[2]
  PIN word_count[3]
    DIRECTION OUTPUT ;
    USE SIGNAL ;
    PORT
      LAYER metal10 ;
        RECT  1.295 375.67 2.095 376.47 ;
    END
  END word_count[3]
  PIN word_count[4]
    DIRECTION OUTPUT ;
    USE SIGNAL ;
    PORT
      LAYER metal10 ;
        RECT  1.295 378.87 2.095 379.67 ;
    END
  END word_count[4]
  PIN word_count[5]
    DIRECTION OUTPUT ;
    USE SIGNAL ;
    PORT
      LAYER metal10 ;
        RECT  1.295 382.07 2.095 382.87 ;
    END
  END word_count[5]
  PIN word_count[6]
    DIRECTION OUTPUT ;
    USE SIGNAL ;
    PORT
      LAYER metal10 ;
        RECT  1.295 385.27 2.095 386.07 ;
    END
  END word_count[6]
  PIN word_count[7]
    DIRECTION OUTPUT ;
    USE SIGNAL ;
    PORT
      LAYER metal10 ;
        RECT  1.295 388.47 2.095 389.27 ;
    END
  END word_count[7]
  PIN word_count[8]
    DIRECTION OUTPUT ;
    USE SIGNAL ;
    PORT
      LAYER metal10 ;
        RECT  1.295 391.67 2.095 392.47 ;
    END
  END word_count[8]
  PIN word_count[9]
    DIRECTION OUTPUT ;
    USE SIGNAL ;
    PORT
      LAYER metal10 ;
        RECT  1.295 394.87 2.095 395.67 ;
    END
  END word_count[9]
  PIN write_data[0]
    DIRECTION INPUT ;
    USE SIGNAL ;
    PORT
      LAYER metal10 ;
        RECT  729.295 543.67 730.095 544.47 ;
    END
  END write_data[0]
  PIN write_data[100]
    DIRECTION INPUT ;
    USE SIGNAL ;
    PORT
      LAYER metal10 ;
        RECT  742.095 569.27 742.895 570.07 ;
    END
  END write_data[100]
  PIN write_data[101]
    DIRECTION INPUT ;
    USE SIGNAL ;
    PORT
      LAYER metal10 ;
        RECT  745.295 569.27 746.095 570.07 ;
    END
  END write_data[101]
  PIN write_data[102]
    DIRECTION INPUT ;
    USE SIGNAL ;
    PORT
      LAYER metal10 ;
        RECT  748.495 569.27 749.295 570.07 ;
    END
  END write_data[102]
  PIN write_data[103]
    DIRECTION INPUT ;
    USE SIGNAL ;
    PORT
      LAYER metal10 ;
        RECT  751.695 569.27 752.495 570.07 ;
    END
  END write_data[103]
  PIN write_data[104]
    DIRECTION INPUT ;
    USE SIGNAL ;
    PORT
      LAYER metal10 ;
        RECT  754.895 569.27 755.695 570.07 ;
    END
  END write_data[104]
  PIN write_data[105]
    DIRECTION INPUT ;
    USE SIGNAL ;
    PORT
      LAYER metal10 ;
        RECT  758.095 569.27 758.895 570.07 ;
    END
  END write_data[105]
  PIN write_data[106]
    DIRECTION INPUT ;
    USE SIGNAL ;
    PORT
      LAYER metal10 ;
        RECT  761.295 569.27 762.095 570.07 ;
    END
  END write_data[106]
  PIN write_data[107]
    DIRECTION INPUT ;
    USE SIGNAL ;
    PORT
      LAYER metal10 ;
        RECT  764.495 569.27 765.295 570.07 ;
    END
  END write_data[107]
  PIN write_data[108]
    DIRECTION INPUT ;
    USE SIGNAL ;
    PORT
      LAYER metal10 ;
        RECT  729.295 572.47 730.095 573.27 ;
    END
  END write_data[108]
  PIN write_data[109]
    DIRECTION INPUT ;
    USE SIGNAL ;
    PORT
      LAYER metal10 ;
        RECT  732.495 572.47 733.295 573.27 ;
    END
  END write_data[109]
  PIN write_data[10]
    DIRECTION INPUT ;
    USE SIGNAL ;
    PORT
      LAYER metal10 ;
        RECT  761.295 543.67 762.095 544.47 ;
    END
  END write_data[10]
  PIN write_data[110]
    DIRECTION INPUT ;
    USE SIGNAL ;
    PORT
      LAYER metal10 ;
        RECT  735.695 572.47 736.495 573.27 ;
    END
  END write_data[110]
  PIN write_data[111]
    DIRECTION INPUT ;
    USE SIGNAL ;
    PORT
      LAYER metal10 ;
        RECT  738.895 572.47 739.695 573.27 ;
    END
  END write_data[111]
  PIN write_data[112]
    DIRECTION INPUT ;
    USE SIGNAL ;
    PORT
      LAYER metal10 ;
        RECT  742.095 572.47 742.895 573.27 ;
    END
  END write_data[112]
  PIN write_data[113]
    DIRECTION INPUT ;
    USE SIGNAL ;
    PORT
      LAYER metal10 ;
        RECT  745.295 572.47 746.095 573.27 ;
    END
  END write_data[113]
  PIN write_data[114]
    DIRECTION INPUT ;
    USE SIGNAL ;
    PORT
      LAYER metal10 ;
        RECT  748.495 572.47 749.295 573.27 ;
    END
  END write_data[114]
  PIN write_data[115]
    DIRECTION INPUT ;
    USE SIGNAL ;
    PORT
      LAYER metal10 ;
        RECT  751.695 572.47 752.495 573.27 ;
    END
  END write_data[115]
  PIN write_data[116]
    DIRECTION INPUT ;
    USE SIGNAL ;
    PORT
      LAYER metal10 ;
        RECT  754.895 572.47 755.695 573.27 ;
    END
  END write_data[116]
  PIN write_data[117]
    DIRECTION INPUT ;
    USE SIGNAL ;
    PORT
      LAYER metal10 ;
        RECT  758.095 572.47 758.895 573.27 ;
    END
  END write_data[117]
  PIN write_data[118]
    DIRECTION INPUT ;
    USE SIGNAL ;
    PORT
      LAYER metal10 ;
        RECT  761.295 572.47 762.095 573.27 ;
    END
  END write_data[118]
  PIN write_data[119]
    DIRECTION INPUT ;
    USE SIGNAL ;
    PORT
      LAYER metal10 ;
        RECT  764.495 572.47 765.295 573.27 ;
    END
  END write_data[119]
  PIN write_data[11]
    DIRECTION INPUT ;
    USE SIGNAL ;
    PORT
      LAYER metal10 ;
        RECT  764.495 543.67 765.295 544.47 ;
    END
  END write_data[11]
  PIN write_data[120]
    DIRECTION INPUT ;
    USE SIGNAL ;
    PORT
      LAYER metal10 ;
        RECT  729.295 575.67 730.095 576.47 ;
    END
  END write_data[120]
  PIN write_data[121]
    DIRECTION INPUT ;
    USE SIGNAL ;
    PORT
      LAYER metal10 ;
        RECT  732.495 575.67 733.295 576.47 ;
    END
  END write_data[121]
  PIN write_data[122]
    DIRECTION INPUT ;
    USE SIGNAL ;
    PORT
      LAYER metal10 ;
        RECT  735.695 575.67 736.495 576.47 ;
    END
  END write_data[122]
  PIN write_data[123]
    DIRECTION INPUT ;
    USE SIGNAL ;
    PORT
      LAYER metal10 ;
        RECT  738.895 575.67 739.695 576.47 ;
    END
  END write_data[123]
  PIN write_data[124]
    DIRECTION INPUT ;
    USE SIGNAL ;
    PORT
      LAYER metal10 ;
        RECT  742.095 575.67 742.895 576.47 ;
    END
  END write_data[124]
  PIN write_data[125]
    DIRECTION INPUT ;
    USE SIGNAL ;
    PORT
      LAYER metal10 ;
        RECT  745.295 575.67 746.095 576.47 ;
    END
  END write_data[125]
  PIN write_data[126]
    DIRECTION INPUT ;
    USE SIGNAL ;
    PORT
      LAYER metal10 ;
        RECT  748.495 575.67 749.295 576.47 ;
    END
  END write_data[126]
  PIN write_data[127]
    DIRECTION INPUT ;
    USE SIGNAL ;
    PORT
      LAYER metal10 ;
        RECT  751.695 575.67 752.495 576.47 ;
    END
  END write_data[127]
  PIN write_data[12]
    DIRECTION INPUT ;
    USE SIGNAL ;
    PORT
      LAYER metal10 ;
        RECT  729.295 546.87 730.095 547.67 ;
    END
  END write_data[12]
  PIN write_data[13]
    DIRECTION INPUT ;
    USE SIGNAL ;
    PORT
      LAYER metal10 ;
        RECT  732.495 546.87 733.295 547.67 ;
    END
  END write_data[13]
  PIN write_data[14]
    DIRECTION INPUT ;
    USE SIGNAL ;
    PORT
      LAYER metal10 ;
        RECT  735.695 546.87 736.495 547.67 ;
    END
  END write_data[14]
  PIN write_data[15]
    DIRECTION INPUT ;
    USE SIGNAL ;
    PORT
      LAYER metal10 ;
        RECT  738.895 546.87 739.695 547.67 ;
    END
  END write_data[15]
  PIN write_data[16]
    DIRECTION INPUT ;
    USE SIGNAL ;
    PORT
      LAYER metal10 ;
        RECT  742.095 546.87 742.895 547.67 ;
    END
  END write_data[16]
  PIN write_data[17]
    DIRECTION INPUT ;
    USE SIGNAL ;
    PORT
      LAYER metal10 ;
        RECT  745.295 546.87 746.095 547.67 ;
    END
  END write_data[17]
  PIN write_data[18]
    DIRECTION INPUT ;
    USE SIGNAL ;
    PORT
      LAYER metal10 ;
        RECT  748.495 546.87 749.295 547.67 ;
    END
  END write_data[18]
  PIN write_data[19]
    DIRECTION INPUT ;
    USE SIGNAL ;
    PORT
      LAYER metal10 ;
        RECT  751.695 546.87 752.495 547.67 ;
    END
  END write_data[19]
  PIN write_data[1]
    DIRECTION INPUT ;
    USE SIGNAL ;
    PORT
      LAYER metal10 ;
        RECT  732.495 543.67 733.295 544.47 ;
    END
  END write_data[1]
  PIN write_data[20]
    DIRECTION INPUT ;
    USE SIGNAL ;
    PORT
      LAYER metal10 ;
        RECT  754.895 546.87 755.695 547.67 ;
    END
  END write_data[20]
  PIN write_data[21]
    DIRECTION INPUT ;
    USE SIGNAL ;
    PORT
      LAYER metal10 ;
        RECT  758.095 546.87 758.895 547.67 ;
    END
  END write_data[21]
  PIN write_data[22]
    DIRECTION INPUT ;
    USE SIGNAL ;
    PORT
      LAYER metal10 ;
        RECT  761.295 546.87 762.095 547.67 ;
    END
  END write_data[22]
  PIN write_data[23]
    DIRECTION INPUT ;
    USE SIGNAL ;
    PORT
      LAYER metal10 ;
        RECT  764.495 546.87 765.295 547.67 ;
    END
  END write_data[23]
  PIN write_data[24]
    DIRECTION INPUT ;
    USE SIGNAL ;
    PORT
      LAYER metal10 ;
        RECT  729.295 550.07 730.095 550.87 ;
    END
  END write_data[24]
  PIN write_data[25]
    DIRECTION INPUT ;
    USE SIGNAL ;
    PORT
      LAYER metal10 ;
        RECT  732.495 550.07 733.295 550.87 ;
    END
  END write_data[25]
  PIN write_data[26]
    DIRECTION INPUT ;
    USE SIGNAL ;
    PORT
      LAYER metal10 ;
        RECT  735.695 550.07 736.495 550.87 ;
    END
  END write_data[26]
  PIN write_data[27]
    DIRECTION INPUT ;
    USE SIGNAL ;
    PORT
      LAYER metal10 ;
        RECT  738.895 550.07 739.695 550.87 ;
    END
  END write_data[27]
  PIN write_data[28]
    DIRECTION INPUT ;
    USE SIGNAL ;
    PORT
      LAYER metal10 ;
        RECT  742.095 550.07 742.895 550.87 ;
    END
  END write_data[28]
  PIN write_data[29]
    DIRECTION INPUT ;
    USE SIGNAL ;
    PORT
      LAYER metal10 ;
        RECT  745.295 550.07 746.095 550.87 ;
    END
  END write_data[29]
  PIN write_data[2]
    DIRECTION INPUT ;
    USE SIGNAL ;
    PORT
      LAYER metal10 ;
        RECT  735.695 543.67 736.495 544.47 ;
    END
  END write_data[2]
  PIN write_data[30]
    DIRECTION INPUT ;
    USE SIGNAL ;
    PORT
      LAYER metal10 ;
        RECT  748.495 550.07 749.295 550.87 ;
    END
  END write_data[30]
  PIN write_data[31]
    DIRECTION INPUT ;
    USE SIGNAL ;
    PORT
      LAYER metal10 ;
        RECT  751.695 550.07 752.495 550.87 ;
    END
  END write_data[31]
  PIN write_data[32]
    DIRECTION INPUT ;
    USE SIGNAL ;
    PORT
      LAYER metal10 ;
        RECT  754.895 550.07 755.695 550.87 ;
    END
  END write_data[32]
  PIN write_data[33]
    DIRECTION INPUT ;
    USE SIGNAL ;
    PORT
      LAYER metal10 ;
        RECT  758.095 550.07 758.895 550.87 ;
    END
  END write_data[33]
  PIN write_data[34]
    DIRECTION INPUT ;
    USE SIGNAL ;
    PORT
      LAYER metal10 ;
        RECT  761.295 550.07 762.095 550.87 ;
    END
  END write_data[34]
  PIN write_data[35]
    DIRECTION INPUT ;
    USE SIGNAL ;
    PORT
      LAYER metal10 ;
        RECT  764.495 550.07 765.295 550.87 ;
    END
  END write_data[35]
  PIN write_data[36]
    DIRECTION INPUT ;
    USE SIGNAL ;
    PORT
      LAYER metal10 ;
        RECT  729.295 553.27 730.095 554.07 ;
    END
  END write_data[36]
  PIN write_data[37]
    DIRECTION INPUT ;
    USE SIGNAL ;
    PORT
      LAYER metal10 ;
        RECT  732.495 553.27 733.295 554.07 ;
    END
  END write_data[37]
  PIN write_data[38]
    DIRECTION INPUT ;
    USE SIGNAL ;
    PORT
      LAYER metal10 ;
        RECT  735.695 553.27 736.495 554.07 ;
    END
  END write_data[38]
  PIN write_data[39]
    DIRECTION INPUT ;
    USE SIGNAL ;
    PORT
      LAYER metal10 ;
        RECT  738.895 553.27 739.695 554.07 ;
    END
  END write_data[39]
  PIN write_data[3]
    DIRECTION INPUT ;
    USE SIGNAL ;
    PORT
      LAYER metal10 ;
        RECT  738.895 543.67 739.695 544.47 ;
    END
  END write_data[3]
  PIN write_data[40]
    DIRECTION INPUT ;
    USE SIGNAL ;
    PORT
      LAYER metal10 ;
        RECT  742.095 553.27 742.895 554.07 ;
    END
  END write_data[40]
  PIN write_data[41]
    DIRECTION INPUT ;
    USE SIGNAL ;
    PORT
      LAYER metal10 ;
        RECT  745.295 553.27 746.095 554.07 ;
    END
  END write_data[41]
  PIN write_data[42]
    DIRECTION INPUT ;
    USE SIGNAL ;
    PORT
      LAYER metal10 ;
        RECT  748.495 553.27 749.295 554.07 ;
    END
  END write_data[42]
  PIN write_data[43]
    DIRECTION INPUT ;
    USE SIGNAL ;
    PORT
      LAYER metal10 ;
        RECT  751.695 553.27 752.495 554.07 ;
    END
  END write_data[43]
  PIN write_data[44]
    DIRECTION INPUT ;
    USE SIGNAL ;
    PORT
      LAYER metal10 ;
        RECT  754.895 553.27 755.695 554.07 ;
    END
  END write_data[44]
  PIN write_data[45]
    DIRECTION INPUT ;
    USE SIGNAL ;
    PORT
      LAYER metal10 ;
        RECT  758.095 553.27 758.895 554.07 ;
    END
  END write_data[45]
  PIN write_data[46]
    DIRECTION INPUT ;
    USE SIGNAL ;
    PORT
      LAYER metal10 ;
        RECT  761.295 553.27 762.095 554.07 ;
    END
  END write_data[46]
  PIN write_data[47]
    DIRECTION INPUT ;
    USE SIGNAL ;
    PORT
      LAYER metal10 ;
        RECT  764.495 553.27 765.295 554.07 ;
    END
  END write_data[47]
  PIN write_data[48]
    DIRECTION INPUT ;
    USE SIGNAL ;
    PORT
      LAYER metal10 ;
        RECT  729.295 556.47 730.095 557.27 ;
    END
  END write_data[48]
  PIN write_data[49]
    DIRECTION INPUT ;
    USE SIGNAL ;
    PORT
      LAYER metal10 ;
        RECT  732.495 556.47 733.295 557.27 ;
    END
  END write_data[49]
  PIN write_data[4]
    DIRECTION INPUT ;
    USE SIGNAL ;
    PORT
      LAYER metal10 ;
        RECT  742.095 543.67 742.895 544.47 ;
    END
  END write_data[4]
  PIN write_data[50]
    DIRECTION INPUT ;
    USE SIGNAL ;
    PORT
      LAYER metal10 ;
        RECT  735.695 556.47 736.495 557.27 ;
    END
  END write_data[50]
  PIN write_data[51]
    DIRECTION INPUT ;
    USE SIGNAL ;
    PORT
      LAYER metal10 ;
        RECT  738.895 556.47 739.695 557.27 ;
    END
  END write_data[51]
  PIN write_data[52]
    DIRECTION INPUT ;
    USE SIGNAL ;
    PORT
      LAYER metal10 ;
        RECT  742.095 556.47 742.895 557.27 ;
    END
  END write_data[52]
  PIN write_data[53]
    DIRECTION INPUT ;
    USE SIGNAL ;
    PORT
      LAYER metal10 ;
        RECT  745.295 556.47 746.095 557.27 ;
    END
  END write_data[53]
  PIN write_data[54]
    DIRECTION INPUT ;
    USE SIGNAL ;
    PORT
      LAYER metal10 ;
        RECT  748.495 556.47 749.295 557.27 ;
    END
  END write_data[54]
  PIN write_data[55]
    DIRECTION INPUT ;
    USE SIGNAL ;
    PORT
      LAYER metal10 ;
        RECT  751.695 556.47 752.495 557.27 ;
    END
  END write_data[55]
  PIN write_data[56]
    DIRECTION INPUT ;
    USE SIGNAL ;
    PORT
      LAYER metal10 ;
        RECT  754.895 556.47 755.695 557.27 ;
    END
  END write_data[56]
  PIN write_data[57]
    DIRECTION INPUT ;
    USE SIGNAL ;
    PORT
      LAYER metal10 ;
        RECT  758.095 556.47 758.895 557.27 ;
    END
  END write_data[57]
  PIN write_data[58]
    DIRECTION INPUT ;
    USE SIGNAL ;
    PORT
      LAYER metal10 ;
        RECT  761.295 556.47 762.095 557.27 ;
    END
  END write_data[58]
  PIN write_data[59]
    DIRECTION INPUT ;
    USE SIGNAL ;
    PORT
      LAYER metal10 ;
        RECT  764.495 556.47 765.295 557.27 ;
    END
  END write_data[59]
  PIN write_data[5]
    DIRECTION INPUT ;
    USE SIGNAL ;
    PORT
      LAYER metal10 ;
        RECT  745.295 543.67 746.095 544.47 ;
    END
  END write_data[5]
  PIN write_data[60]
    DIRECTION INPUT ;
    USE SIGNAL ;
    PORT
      LAYER metal10 ;
        RECT  729.295 559.67 730.095 560.47 ;
    END
  END write_data[60]
  PIN write_data[61]
    DIRECTION INPUT ;
    USE SIGNAL ;
    PORT
      LAYER metal10 ;
        RECT  732.495 559.67 733.295 560.47 ;
    END
  END write_data[61]
  PIN write_data[62]
    DIRECTION INPUT ;
    USE SIGNAL ;
    PORT
      LAYER metal10 ;
        RECT  735.695 559.67 736.495 560.47 ;
    END
  END write_data[62]
  PIN write_data[63]
    DIRECTION INPUT ;
    USE SIGNAL ;
    PORT
      LAYER metal10 ;
        RECT  738.895 559.67 739.695 560.47 ;
    END
  END write_data[63]
  PIN write_data[64]
    DIRECTION INPUT ;
    USE SIGNAL ;
    PORT
      LAYER metal10 ;
        RECT  742.095 559.67 742.895 560.47 ;
    END
  END write_data[64]
  PIN write_data[65]
    DIRECTION INPUT ;
    USE SIGNAL ;
    PORT
      LAYER metal10 ;
        RECT  745.295 559.67 746.095 560.47 ;
    END
  END write_data[65]
  PIN write_data[66]
    DIRECTION INPUT ;
    USE SIGNAL ;
    PORT
      LAYER metal10 ;
        RECT  748.495 559.67 749.295 560.47 ;
    END
  END write_data[66]
  PIN write_data[67]
    DIRECTION INPUT ;
    USE SIGNAL ;
    PORT
      LAYER metal10 ;
        RECT  751.695 559.67 752.495 560.47 ;
    END
  END write_data[67]
  PIN write_data[68]
    DIRECTION INPUT ;
    USE SIGNAL ;
    PORT
      LAYER metal10 ;
        RECT  754.895 559.67 755.695 560.47 ;
    END
  END write_data[68]
  PIN write_data[69]
    DIRECTION INPUT ;
    USE SIGNAL ;
    PORT
      LAYER metal10 ;
        RECT  758.095 559.67 758.895 560.47 ;
    END
  END write_data[69]
  PIN write_data[6]
    DIRECTION INPUT ;
    USE SIGNAL ;
    PORT
      LAYER metal10 ;
        RECT  748.495 543.67 749.295 544.47 ;
    END
  END write_data[6]
  PIN write_data[70]
    DIRECTION INPUT ;
    USE SIGNAL ;
    PORT
      LAYER metal10 ;
        RECT  761.295 559.67 762.095 560.47 ;
    END
  END write_data[70]
  PIN write_data[71]
    DIRECTION INPUT ;
    USE SIGNAL ;
    PORT
      LAYER metal10 ;
        RECT  764.495 559.67 765.295 560.47 ;
    END
  END write_data[71]
  PIN write_data[72]
    DIRECTION INPUT ;
    USE SIGNAL ;
    PORT
      LAYER metal10 ;
        RECT  729.295 562.87 730.095 563.67 ;
    END
  END write_data[72]
  PIN write_data[73]
    DIRECTION INPUT ;
    USE SIGNAL ;
    PORT
      LAYER metal10 ;
        RECT  732.495 562.87 733.295 563.67 ;
    END
  END write_data[73]
  PIN write_data[74]
    DIRECTION INPUT ;
    USE SIGNAL ;
    PORT
      LAYER metal10 ;
        RECT  735.695 562.87 736.495 563.67 ;
    END
  END write_data[74]
  PIN write_data[75]
    DIRECTION INPUT ;
    USE SIGNAL ;
    PORT
      LAYER metal10 ;
        RECT  738.895 562.87 739.695 563.67 ;
    END
  END write_data[75]
  PIN write_data[76]
    DIRECTION INPUT ;
    USE SIGNAL ;
    PORT
      LAYER metal10 ;
        RECT  742.095 562.87 742.895 563.67 ;
    END
  END write_data[76]
  PIN write_data[77]
    DIRECTION INPUT ;
    USE SIGNAL ;
    PORT
      LAYER metal10 ;
        RECT  745.295 562.87 746.095 563.67 ;
    END
  END write_data[77]
  PIN write_data[78]
    DIRECTION INPUT ;
    USE SIGNAL ;
    PORT
      LAYER metal10 ;
        RECT  748.495 562.87 749.295 563.67 ;
    END
  END write_data[78]
  PIN write_data[79]
    DIRECTION INPUT ;
    USE SIGNAL ;
    PORT
      LAYER metal10 ;
        RECT  751.695 562.87 752.495 563.67 ;
    END
  END write_data[79]
  PIN write_data[7]
    DIRECTION INPUT ;
    USE SIGNAL ;
    PORT
      LAYER metal10 ;
        RECT  751.695 543.67 752.495 544.47 ;
    END
  END write_data[7]
  PIN write_data[80]
    DIRECTION INPUT ;
    USE SIGNAL ;
    PORT
      LAYER metal10 ;
        RECT  754.895 562.87 755.695 563.67 ;
    END
  END write_data[80]
  PIN write_data[81]
    DIRECTION INPUT ;
    USE SIGNAL ;
    PORT
      LAYER metal10 ;
        RECT  758.095 562.87 758.895 563.67 ;
    END
  END write_data[81]
  PIN write_data[82]
    DIRECTION INPUT ;
    USE SIGNAL ;
    PORT
      LAYER metal10 ;
        RECT  761.295 562.87 762.095 563.67 ;
    END
  END write_data[82]
  PIN write_data[83]
    DIRECTION INPUT ;
    USE SIGNAL ;
    PORT
      LAYER metal10 ;
        RECT  764.495 562.87 765.295 563.67 ;
    END
  END write_data[83]
  PIN write_data[84]
    DIRECTION INPUT ;
    USE SIGNAL ;
    PORT
      LAYER metal10 ;
        RECT  729.295 566.07 730.095 566.87 ;
    END
  END write_data[84]
  PIN write_data[85]
    DIRECTION INPUT ;
    USE SIGNAL ;
    PORT
      LAYER metal10 ;
        RECT  732.495 566.07 733.295 566.87 ;
    END
  END write_data[85]
  PIN write_data[86]
    DIRECTION INPUT ;
    USE SIGNAL ;
    PORT
      LAYER metal10 ;
        RECT  735.695 566.07 736.495 566.87 ;
    END
  END write_data[86]
  PIN write_data[87]
    DIRECTION INPUT ;
    USE SIGNAL ;
    PORT
      LAYER metal10 ;
        RECT  738.895 566.07 739.695 566.87 ;
    END
  END write_data[87]
  PIN write_data[88]
    DIRECTION INPUT ;
    USE SIGNAL ;
    PORT
      LAYER metal10 ;
        RECT  742.095 566.07 742.895 566.87 ;
    END
  END write_data[88]
  PIN write_data[89]
    DIRECTION INPUT ;
    USE SIGNAL ;
    PORT
      LAYER metal10 ;
        RECT  745.295 566.07 746.095 566.87 ;
    END
  END write_data[89]
  PIN write_data[8]
    DIRECTION INPUT ;
    USE SIGNAL ;
    PORT
      LAYER metal10 ;
        RECT  754.895 543.67 755.695 544.47 ;
    END
  END write_data[8]
  PIN write_data[90]
    DIRECTION INPUT ;
    USE SIGNAL ;
    PORT
      LAYER metal10 ;
        RECT  748.495 566.07 749.295 566.87 ;
    END
  END write_data[90]
  PIN write_data[91]
    DIRECTION INPUT ;
    USE SIGNAL ;
    PORT
      LAYER metal10 ;
        RECT  751.695 566.07 752.495 566.87 ;
    END
  END write_data[91]
  PIN write_data[92]
    DIRECTION INPUT ;
    USE SIGNAL ;
    PORT
      LAYER metal10 ;
        RECT  754.895 566.07 755.695 566.87 ;
    END
  END write_data[92]
  PIN write_data[93]
    DIRECTION INPUT ;
    USE SIGNAL ;
    PORT
      LAYER metal10 ;
        RECT  758.095 566.07 758.895 566.87 ;
    END
  END write_data[93]
  PIN write_data[94]
    DIRECTION INPUT ;
    USE SIGNAL ;
    PORT
      LAYER metal10 ;
        RECT  761.295 566.07 762.095 566.87 ;
    END
  END write_data[94]
  PIN write_data[95]
    DIRECTION INPUT ;
    USE SIGNAL ;
    PORT
      LAYER metal10 ;
        RECT  764.495 566.07 765.295 566.87 ;
    END
  END write_data[95]
  PIN write_data[96]
    DIRECTION INPUT ;
    USE SIGNAL ;
    PORT
      LAYER metal10 ;
        RECT  729.295 569.27 730.095 570.07 ;
    END
  END write_data[96]
  PIN write_data[97]
    DIRECTION INPUT ;
    USE SIGNAL ;
    PORT
      LAYER metal10 ;
        RECT  732.495 569.27 733.295 570.07 ;
    END
  END write_data[97]
  PIN write_data[98]
    DIRECTION INPUT ;
    USE SIGNAL ;
    PORT
      LAYER metal10 ;
        RECT  735.695 569.27 736.495 570.07 ;
    END
  END write_data[98]
  PIN write_data[99]
    DIRECTION INPUT ;
    USE SIGNAL ;
    PORT
      LAYER metal10 ;
        RECT  738.895 569.27 739.695 570.07 ;
    END
  END write_data[99]
  PIN write_data[9]
    DIRECTION INPUT ;
    USE SIGNAL ;
    PORT
      LAYER metal10 ;
        RECT  758.095 543.67 758.895 544.47 ;
    END
  END write_data[9]
  PIN write_index[0]
    DIRECTION INPUT ;
    USE SIGNAL ;
    PORT
      LAYER metal10 ;
        RECT  1.295 398.07 2.095 398.87 ;
    END
  END write_index[0]
  PIN write_index[1]
    DIRECTION INPUT ;
    USE SIGNAL ;
    PORT
      LAYER metal10 ;
        RECT  1.295 401.27 2.095 402.07 ;
    END
  END write_index[1]
  PIN write_index[2]
    DIRECTION INPUT ;
    USE SIGNAL ;
    PORT
      LAYER metal10 ;
        RECT  1.295 404.47 2.095 405.27 ;
    END
  END write_index[2]
  PIN write_index[3]
    DIRECTION INPUT ;
    USE SIGNAL ;
    PORT
      LAYER metal10 ;
        RECT  1.295 407.67 2.095 408.47 ;
    END
  END write_index[3]
  PIN write_index[4]
    DIRECTION INPUT ;
    USE SIGNAL ;
    PORT
      LAYER metal10 ;
        RECT  1.295 410.87 2.095 411.67 ;
    END
  END write_index[4]
  PIN write_index[5]
    DIRECTION INPUT ;
    USE SIGNAL ;
    PORT
      LAYER metal10 ;
        RECT  1.295 414.07 2.095 414.87 ;
    END
  END write_index[5]
  PIN write_index[6]
    DIRECTION INPUT ;
    USE SIGNAL ;
    PORT
      LAYER metal10 ;
        RECT  1.295 417.27 2.095 418.07 ;
    END
  END write_index[6]
  PIN write_index[7]
    DIRECTION INPUT ;
    USE SIGNAL ;
    PORT
      LAYER metal10 ;
        RECT  1.295 420.47 2.095 421.27 ;
    END
  END write_index[7]
  PIN write_index[8]
    DIRECTION INPUT ;
    USE SIGNAL ;
    PORT
      LAYER metal10 ;
        RECT  1.295 423.67 2.095 424.47 ;
    END
  END write_index[8]
  PIN write_index[9]
    DIRECTION INPUT ;
    USE SIGNAL ;
    PORT
      LAYER metal10 ;
        RECT  1.295 426.87 2.095 427.67 ;
    END
  END write_index[9]
  PIN write_ready
    DIRECTION OUTPUT ;
    USE SIGNAL ;
    PORT
      LAYER metal10 ;
        RECT  1.295 430.07 2.095 430.87 ;
    END
  END write_ready
  PIN write_valid
    DIRECTION INPUT ;
    USE SIGNAL ;
    PORT
      LAYER metal10 ;
        RECT  1.295 433.27 2.095 434.07 ;
    END
  END write_valid
  PIN VDD
    DIRECTION INOUT ;
    USE POWER ;
    PORT
      LAYER metal7 ;
        RECT  20.14 1087.3 1099.91 1088.7 ;
        RECT  20.14 1057.3 1099.91 1058.7 ;
        RECT  20.14 1027.3 1099.91 1028.7 ;
        RECT  20.14 997.3 1099.91 998.7 ;
        RECT  20.14 967.3 1099.91 968.7 ;
        RECT  20.14 937.3 1099.91 938.7 ;
        RECT  20.14 907.3 1099.91 908.7 ;
        RECT  20.14 877.3 1099.91 878.7 ;
        RECT  20.14 847.3 1099.91 848.7 ;
        RECT  20.14 817.3 1099.91 818.7 ;
        RECT  20.14 787.3 1099.91 788.7 ;
        RECT  20.14 757.3 1099.91 758.7 ;
        RECT  20.14 727.3 1099.91 728.7 ;
        RECT  20.14 697.3 1099.91 698.7 ;
        RECT  20.14 667.3 1099.91 668.7 ;
        RECT  20.14 637.3 1099.91 638.7 ;
        RECT  20.14 607.3 1099.91 608.7 ;
        RECT  20.14 577.3 1099.91 578.7 ;
        RECT  20.14 547.3 1099.91 548.7 ;
        RECT  20.14 517.3 1099.91 518.7 ;
        RECT  20.14 487.3 1099.91 488.7 ;
        RECT  20.14 457.3 1099.91 458.7 ;
        RECT  20.14 427.3 1099.91 428.7 ;
        RECT  20.14 397.3 1099.91 398.7 ;
        RECT  20.14 367.3 1099.91 368.7 ;
        RECT  20.14 337.3 1099.91 338.7 ;
        RECT  20.14 307.3 1099.91 308.7 ;
        RECT  20.14 277.3 1099.91 278.7 ;
        RECT  20.14 247.3 1099.91 248.7 ;
        RECT  20.14 217.3 1099.91 218.7 ;
        RECT  20.14 187.3 1099.91 188.7 ;
        RECT  20.14 157.3 1099.91 158.7 ;
        RECT  20.14 127.3 1099.91 128.7 ;
        RECT  20.14 97.3 1099.91 98.7 ;
        RECT  20.14 67.3 1099.91 68.7 ;
        RECT  20.14 37.3 1099.91 38.7 ;
    END
  END VDD
  PIN VSS
    DIRECTION INOUT ;
    USE GROUND ;
    PORT
      LAYER metal7 ;
        RECT  20.14 1072.3 1099.91 1073.7 ;
        RECT  20.14 1042.3 1099.91 1043.7 ;
        RECT  20.14 1012.3 1099.91 1013.7 ;
        RECT  20.14 982.3 1099.91 983.7 ;
        RECT  20.14 952.3 1099.91 953.7 ;
        RECT  20.14 922.3 1099.91 923.7 ;
        RECT  20.14 892.3 1099.91 893.7 ;
        RECT  20.14 862.3 1099.91 863.7 ;
        RECT  20.14 832.3 1099.91 833.7 ;
        RECT  20.14 802.3 1099.91 803.7 ;
        RECT  20.14 772.3 1099.91 773.7 ;
        RECT  20.14 742.3 1099.91 743.7 ;
        RECT  20.14 712.3 1099.91 713.7 ;
        RECT  20.14 682.3 1099.91 683.7 ;
        RECT  20.14 652.3 1099.91 653.7 ;
        RECT  20.14 622.3 1099.91 623.7 ;
        RECT  20.14 592.3 1099.91 593.7 ;
        RECT  20.14 562.3 1099.91 563.7 ;
        RECT  20.14 532.3 1099.91 533.7 ;
        RECT  20.14 502.3 1099.91 503.7 ;
        RECT  20.14 472.3 1099.91 473.7 ;
        RECT  20.14 442.3 1099.91 443.7 ;
        RECT  20.14 412.3 1099.91 413.7 ;
        RECT  20.14 382.3 1099.91 383.7 ;
        RECT  20.14 352.3 1099.91 353.7 ;
        RECT  20.14 322.3 1099.91 323.7 ;
        RECT  20.14 292.3 1099.91 293.7 ;
        RECT  20.14 262.3 1099.91 263.7 ;
        RECT  20.14 232.3 1099.91 233.7 ;
        RECT  20.14 202.3 1099.91 203.7 ;
        RECT  20.14 172.3 1099.91 173.7 ;
        RECT  20.14 142.3 1099.91 143.7 ;
        RECT  20.14 112.3 1099.91 113.7 ;
        RECT  20.14 82.3 1099.91 83.7 ;
        RECT  20.14 52.3 1099.91 53.7 ;
        RECT  20.14 22.3 1099.91 23.7 ;
    END
  END VSS
  OBS
    LAYER metal1 ;
     RECT  0.495 20.47 1099.91 1099.085 ;
    LAYER metal2 ;
     RECT  0.495 20.47 1099.91 1099.085 ;
    LAYER metal3 ;
     RECT  0.495 20.47 1099.91 1099.085 ;
    LAYER metal4 ;
     RECT  0.495 20.47 1099.91 1099.085 ;
    LAYER metal5 ;
     RECT  0.495 20.47 1099.91 1099.085 ;
    LAYER metal6 ;
     RECT  0.495 20.47 1099.91 1099.085 ;
    LAYER metal7 ;
     RECT  0.495 20.47 1099.91 1099.085 ;
    LAYER metal8 ;
     RECT  0.495 20.47 1099.91 1099.085 ;
    LAYER metal9 ;
     RECT  0.495 20.47 1099.91 1099.085 ;
    LAYER metal10 ;
     RECT  0.495 20.47 1099.91 1099.085 ;
  END
END transaction6k
END LIBRARY
